One B-rep face of a CAD part: STEP entity #211.
In plain terms, the planar face has unit normal (0, 0, 1).
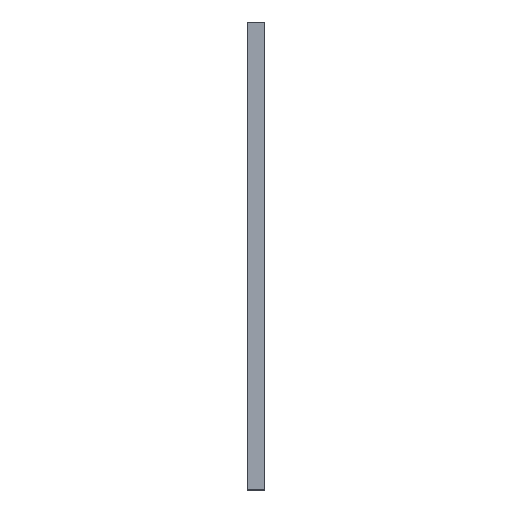
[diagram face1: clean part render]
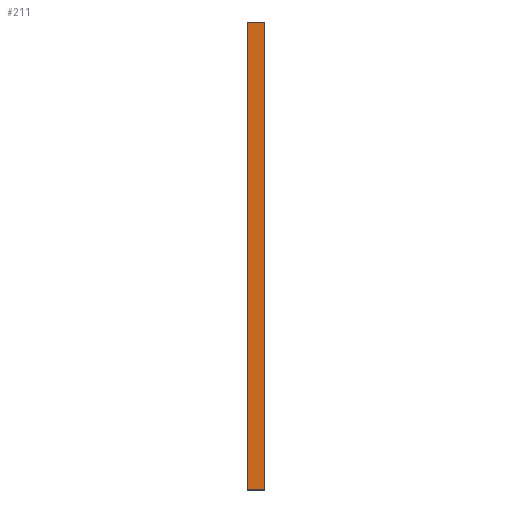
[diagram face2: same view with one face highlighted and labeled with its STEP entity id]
Its self-contained STEP definition (entity closure, numbers rounded to 3 decimals):
#32 = PLANE('',#33);
#33 = AXIS2_PLACEMENT_3D('',#34,#35,#36);
#34 = CARTESIAN_POINT('',(34.,-66.,212.));
#35 = DIRECTION('',(0.,-1.,0.));
#36 = DIRECTION('',(0.,0.,1.));
#57 = VERTEX_POINT('',#58);
#58 = CARTESIAN_POINT('',(38.,-66.,256.));
#72 = PLANE('',#73);
#73 = AXIS2_PLACEMENT_3D('',#74,#75,#76);
#74 = CARTESIAN_POINT('',(38.,-13.,234.));
#75 = DIRECTION('',(-1.,-0.,-0.));
#76 = DIRECTION('',(0.,0.,-1.));
#84 = EDGE_CURVE('',#85,#57,#87,.T.);
#85 = VERTEX_POINT('',#86);
#86 = CARTESIAN_POINT('',(34.,-66.,256.));
#87 = SURFACE_CURVE('',#88,(#92,#99),.PCURVE_S1.);
#88 = LINE('',#89,#90);
#89 = CARTESIAN_POINT('',(34.,-66.,256.));
#90 = VECTOR('',#91,1.);
#91 = DIRECTION('',(1.,0.,0.));
#92 = PCURVE('',#32,#93);
#93 = DEFINITIONAL_REPRESENTATION('',(#94),#98);
#94 = LINE('',#95,#96);
#95 = CARTESIAN_POINT('',(44.,0.));
#96 = VECTOR('',#97,1.);
#97 = DIRECTION('',(0.,-1.));
#98 = ( GEOMETRIC_REPRESENTATION_CONTEXT(2) 
PARAMETRIC_REPRESENTATION_CONTEXT() REPRESENTATION_CONTEXT('2D SPACE',''
  ) );
#99 = PCURVE('',#100,#105);
#100 = PLANE('',#101);
#101 = AXIS2_PLACEMENT_3D('',#102,#103,#104);
#102 = CARTESIAN_POINT('',(34.,-66.,256.));
#103 = DIRECTION('',(0.,0.,1.));
#104 = DIRECTION('',(0.,1.,0.));
#105 = DEFINITIONAL_REPRESENTATION('',(#106),#110);
#106 = LINE('',#107,#108);
#107 = CARTESIAN_POINT('',(0.,0.));
#108 = VECTOR('',#109,1.);
#109 = DIRECTION('',(0.,-1.));
#110 = ( GEOMETRIC_REPRESENTATION_CONTEXT(2) 
PARAMETRIC_REPRESENTATION_CONTEXT() REPRESENTATION_CONTEXT('2D SPACE',''
  ) );
#126 = PLANE('',#127);
#127 = AXIS2_PLACEMENT_3D('',#128,#129,#130);
#128 = CARTESIAN_POINT('',(34.,-13.,234.));
#129 = DIRECTION('',(-1.,-0.,-0.));
#130 = DIRECTION('',(0.,0.,-1.));
#211 = ADVANCED_FACE('',(#212),#100,.T.);
#212 = FACE_BOUND('',#213,.T.);
#213 = EDGE_LOOP('',(#214,#215,#238,#266));
#214 = ORIENTED_EDGE('',*,*,#84,.T.);
#215 = ORIENTED_EDGE('',*,*,#216,.T.);
#216 = EDGE_CURVE('',#57,#217,#219,.T.);
#217 = VERTEX_POINT('',#218);
#218 = CARTESIAN_POINT('',(38.,40.,256.));
#219 = SURFACE_CURVE('',#220,(#224,#231),.PCURVE_S1.);
#220 = LINE('',#221,#222);
#221 = CARTESIAN_POINT('',(38.,-66.,256.));
#222 = VECTOR('',#223,1.);
#223 = DIRECTION('',(0.,1.,0.));
#224 = PCURVE('',#100,#225);
#225 = DEFINITIONAL_REPRESENTATION('',(#226),#230);
#226 = LINE('',#227,#228);
#227 = CARTESIAN_POINT('',(0.,-4.));
#228 = VECTOR('',#229,1.);
#229 = DIRECTION('',(1.,0.));
#230 = ( GEOMETRIC_REPRESENTATION_CONTEXT(2) 
PARAMETRIC_REPRESENTATION_CONTEXT() REPRESENTATION_CONTEXT('2D SPACE',''
  ) );
#231 = PCURVE('',#72,#232);
#232 = DEFINITIONAL_REPRESENTATION('',(#233),#237);
#233 = LINE('',#234,#235);
#234 = CARTESIAN_POINT('',(-22.,53.));
#235 = VECTOR('',#236,1.);
#236 = DIRECTION('',(0.,-1.));
#237 = ( GEOMETRIC_REPRESENTATION_CONTEXT(2) 
PARAMETRIC_REPRESENTATION_CONTEXT() REPRESENTATION_CONTEXT('2D SPACE',''
  ) );
#238 = ORIENTED_EDGE('',*,*,#239,.F.);
#239 = EDGE_CURVE('',#240,#217,#242,.T.);
#240 = VERTEX_POINT('',#241);
#241 = CARTESIAN_POINT('',(34.,40.,256.));
#242 = SURFACE_CURVE('',#243,(#247,#254),.PCURVE_S1.);
#243 = LINE('',#244,#245);
#244 = CARTESIAN_POINT('',(34.,40.,256.));
#245 = VECTOR('',#246,1.);
#246 = DIRECTION('',(1.,0.,0.));
#247 = PCURVE('',#100,#248);
#248 = DEFINITIONAL_REPRESENTATION('',(#249),#253);
#249 = LINE('',#250,#251);
#250 = CARTESIAN_POINT('',(106.,0.));
#251 = VECTOR('',#252,1.);
#252 = DIRECTION('',(0.,-1.));
#253 = ( GEOMETRIC_REPRESENTATION_CONTEXT(2) 
PARAMETRIC_REPRESENTATION_CONTEXT() REPRESENTATION_CONTEXT('2D SPACE',''
  ) );
#254 = PCURVE('',#255,#260);
#255 = PLANE('',#256);
#256 = AXIS2_PLACEMENT_3D('',#257,#258,#259);
#257 = CARTESIAN_POINT('',(34.,40.,256.));
#258 = DIRECTION('',(-0.,1.,0.));
#259 = DIRECTION('',(0.,0.,-1.));
#260 = DEFINITIONAL_REPRESENTATION('',(#261),#265);
#261 = LINE('',#262,#263);
#262 = CARTESIAN_POINT('',(0.,0.));
#263 = VECTOR('',#264,1.);
#264 = DIRECTION('',(0.,-1.));
#265 = ( GEOMETRIC_REPRESENTATION_CONTEXT(2) 
PARAMETRIC_REPRESENTATION_CONTEXT() REPRESENTATION_CONTEXT('2D SPACE',''
  ) );
#266 = ORIENTED_EDGE('',*,*,#267,.F.);
#267 = EDGE_CURVE('',#85,#240,#268,.T.);
#268 = SURFACE_CURVE('',#269,(#273,#280),.PCURVE_S1.);
#269 = LINE('',#270,#271);
#270 = CARTESIAN_POINT('',(34.,-66.,256.));
#271 = VECTOR('',#272,1.);
#272 = DIRECTION('',(0.,1.,0.));
#273 = PCURVE('',#100,#274);
#274 = DEFINITIONAL_REPRESENTATION('',(#275),#279);
#275 = LINE('',#276,#277);
#276 = CARTESIAN_POINT('',(0.,0.));
#277 = VECTOR('',#278,1.);
#278 = DIRECTION('',(1.,0.));
#279 = ( GEOMETRIC_REPRESENTATION_CONTEXT(2) 
PARAMETRIC_REPRESENTATION_CONTEXT() REPRESENTATION_CONTEXT('2D SPACE',''
  ) );
#280 = PCURVE('',#126,#281);
#281 = DEFINITIONAL_REPRESENTATION('',(#282),#286);
#282 = LINE('',#283,#284);
#283 = CARTESIAN_POINT('',(-22.,53.));
#284 = VECTOR('',#285,1.);
#285 = DIRECTION('',(0.,-1.));
#286 = ( GEOMETRIC_REPRESENTATION_CONTEXT(2) 
PARAMETRIC_REPRESENTATION_CONTEXT() REPRESENTATION_CONTEXT('2D SPACE',''
  ) );
